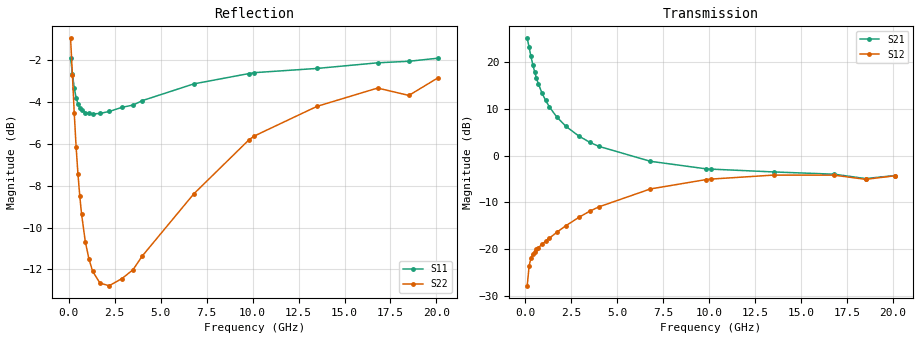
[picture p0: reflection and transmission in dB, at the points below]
!  Infineon Technologies AG
! BFR380L3 , PF131585-7, No.6, Th 09.10.01, soldered on pcb-board, measured with PP GSG850
!  Vce=0.5 V,  Ic=6.0 mA
! Common Emitter S-Parameters:  15. November 2001
#  GHz  S  MA  R  50
! f  S11  S21  S12  S22
! GHz  Mag  Ang  Mag  Ang  Mag  Ang  Mag  Ang
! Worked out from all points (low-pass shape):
!   201 points, 100 MHz to 20.1 GHz, reference 50 ohm
!   highest |S21| = 25.04 dB at 100 MHz (marker M1); lowest = -4.9 dB at 18.5 GHz (marker M2)
!   |S21| within 3 dB of the highest: start of sweep to 258 MHz
!   lowest |S11| = -4.6 dB at 1.3 GHz (marker M3), VSWR 3.88, Z = 12.9 - j2.18 ohm
!   |S11| at or under -10 dB: nowhere
!   |S22| runs from -12.8 to -1.0 dB; largest |S21 - S12| = 18
!   S11 on the Smith chart (normalised r, x): 100 MHz: 0.76, -2.32; 300 MHz: 0.31, -0.77; 900 MHz: 0.26, -0.17; 4 GHz: 0.26, +0.39; 9.8 GHz: 0.37, +1.16; 20.1 GHz: 0.93, +2.59
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0.1  0.8021 -43.1  17.85 153.5  0.04072 67.8  0.8934 -29.9
0.2  0.736 -77.1  14.4 133.9  0.06581 53.6  0.7309 -52.4
0.3  0.68 -101.1  11.5 121.1  0.08031 45.8  0.5922 -68.1
0.4  0.6451 -117.9  9.383 112.1  0.08847 41.6  0.4934 -79.9
0.5  0.6231 -130.3  7.852 105.4  0.09426 39.7  0.4247 -89.1
0.6  0.6105 -140.1  6.716 100.3  0.09947 38.8  0.3758 -96.7
0.7  0.6027 -147.7  5.867 95.9  0.1037 38.7  0.3399 -103.2
0.9  0.5944 -159.2  4.665 89.1  0.1126 39.6  0.2927 -113.9
1.1  0.5917 -167.7  3.881 83.5  0.1215 40.9  0.266 -122.5
1.3  0.5898 -174.7  3.32 78.6  0.1308 42.4  0.2487 -129.7
1.7  0.5917 174.4  2.59 70.2  0.1511 44.6  0.233 -141.1
2.2  0.5981 163.6  2.052 61.2  0.178 46.2  0.2298 -151.8
2.9  0.6118 151.0  1.619 50.1  0.2181 46.5  0.239 -163.5
3.5  0.6195 141.5  1.385 41.8  0.2546 45.3  0.251 -171.0
4  0.6347 134.6  1.253 35.8  0.2831 43.6  0.2705 -177.8
6.8  0.6958 102.1  0.868 9.5  0.4398 28.3  0.3804 149.7
9.799999  0.7364 78.3  0.7223 -7.3  0.5525 9.4  0.5117 121.9
10.1  0.7401 76.5  0.716 -8.5  0.5604 7.6  0.5229 119.3
13.5  0.7574 59.0  0.6682 -22.3  0.6183 -12.5  0.615 93.0
16.8  0.7812 47.3  0.632 -33.3  0.6172 -27.6  0.6801 73.3
18.5  0.7878 45.5  0.5674 -40.7  0.5567 -35.8  0.6531 68.3
20.1  0.8014 38.3  0.6117 -44.1  0.608 -40.5  0.72 58.2
